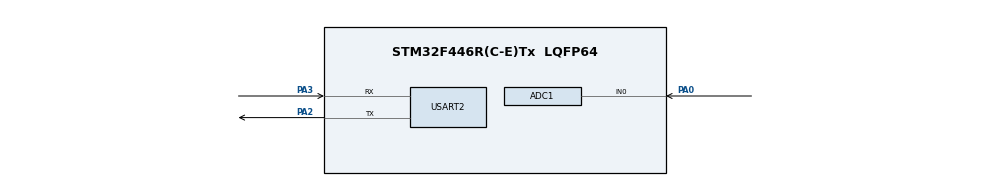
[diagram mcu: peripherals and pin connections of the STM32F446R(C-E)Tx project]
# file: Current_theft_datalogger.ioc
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ADC1.Channel-0\#ChannelRegularConversion=ADC_CHANNEL_0
ADC1.NbrOfConversionFlag=1
ADC1.Rank-0\#ChannelRegularConversion=1
ADC1.SamplingTime-0\#ChannelRegularConversion=ADC_SAMPLETIME_3CYCLES
ADC1.master=1
Dma.Request0=USART2_RX
Dma.Request1=USART2_TX
Dma.USART2_RX.0.Direction=DMA_PERIPH_TO_MEMORY
Dma.USART2_RX.0.FIFOMode=DMA_FIFOMODE_DISABLE
Dma.USART2_RX.0.Instance=DMA1_Stream5
Dma.USART2_RX.0.MemDataAlignment=DMA_MDATAALIGN_BYTE
Dma.USART2_RX.0.MemInc=DMA_MINC_ENABLE
Dma.USART2_RX.0.Mode=DMA_NORMAL
Dma.USART2_RX.0.PeriphDataAlignment=DMA_PDATAALIGN_BYTE
Dma.USART2_RX.0.PeriphInc=DMA_PINC_DISABLE
Dma.USART2_RX.0.Priority=DMA_PRIORITY_LOW
Dma.USART2_TX.1.Direction=DMA_MEMORY_TO_PERIPH
Dma.USART2_TX.1.FIFOMode=DMA_FIFOMODE_DISABLE
Dma.USART2_TX.1.Instance=DMA1_Stream6
Dma.USART2_TX.1.MemDataAlignment=DMA_MDATAALIGN_BYTE
Dma.USART2_TX.1.MemInc=DMA_MINC_ENABLE
Dma.USART2_TX.1.Mode=DMA_NORMAL
Dma.USART2_TX.1.PeriphDataAlignment=DMA_PDATAALIGN_BYTE
Dma.USART2_TX.1.PeriphInc=DMA_PINC_DISABLE
Dma.USART2_TX.1.Priority=DMA_PRIORITY_LOW
Mcu.Family=STM32F4
Mcu.Name=STM32F446R(C-E)Tx
Mcu.Package=LQFP64
NVIC.DMA1_Stream5_IRQn=true\:0\:0\:false\:false\:true\:false\:true\:true
NVIC.DMA1_Stream6_IRQn=true\:0\:0\:false\:false\:true\:false\:true\:true
NVIC.PriorityGroup=NVIC_PRIORITYGROUP_4
PA0-WKUP.Signal=ADCx_IN0
PA2.Mode=Asynchronous
PA2.Signal=USART2_TX
PA3.Mode=Asynchronous
PA3.Signal=USART2_RX
PC13.Mode=SYS_WakeUp1
PC13.Signal=SYS_WKUP1
PC14-OSC32_IN.Mode=LSE-External-Oscillator
PC14-OSC32_IN.Signal=RCC_OSC32_IN
PC15-OSC32_OUT.Mode=LSE-External-Oscillator
PC15-OSC32_OUT.Signal=RCC_OSC32_OUT
PH0-OSC_IN.Mode=HSE-External-Oscillator
PH0-OSC_IN.Signal=RCC_OSC_IN
PH1-OSC_OUT.Mode=HSE-External-Oscillator
PH1-OSC_OUT.Signal=RCC_OSC_OUT
ProjectManager.HeapSize=0x200
ProjectManager.StackSize=0x400
ProjectManager.TargetToolchain=STM32CubeIDE
RCC.CortexFreq_Value=16000000
RCC.USBFreq_Value=96000000
RCC.VCOOutputFreq_Value=192000000
SH.ADCx_IN0.0=ADC1_IN0,IN0
USART2.VirtualMode=VM_ASYNC
board=custom

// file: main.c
/* USER CODE BEGIN Header */
/**
  ******************************************************************************
  * @file           : main.c
  * @brief          : ACS712 Current Sensor Example with UART Print
  ******************************************************************************
  * @attention
  *
  * This code reads ACS712 output on PA0, converts to current, and prints over UART2.
  *
  ******************************************************************************
  */
/* USER CODE END Header */

#include "main.h"
#include <stdio.h>
#include <string.h>
#include "NanoEdgeAI.h"
#define VREF             3.3f
#define ADC_RESOLUTION   4095.0f
#define ACS_SENSITIVITY  0.185f   // 5A version = 185 mV/A

ADC_HandleTypeDef hadc1;
UART_HandleTypeDef huart2;

float ACS_OFFSET_V = 2.50f;   // Will calibrate at startup
char msg[64];

void SystemClock_Config(void);
static void MX_GPIO_Init(void);
static void MX_USART2_UART_Init(void);
static void MX_ADC1_Init(void);
void Error_Handler(void);

int main(void)
{
  /* MCU Configuration--------------------------------------------------------*/
  HAL_Init();
  SystemClock_Config();
  MX_GPIO_Init();
  MX_USART2_UART_Init();
  MX_ADC1_Init();

  /* Start ADC */
  HAL_ADC_Start(&hadc1);

  /* Calibrate ACS712 offset at startup (average 100 samples, no current) */
  uint32_t sum = 0;
  for (int i = 0; i < 100; i++)
  {
    HAL_ADC_PollForConversion(&hadc1, HAL_MAX_DELAY);
    sum += HAL_ADC_GetValue(&hadc1);
    HAL_Delay(1);
  }
  uint32_t avgAdc = sum / 100;
  ACS_OFFSET_V = ((float)avgAdc * VREF) / ADC_RESOLUTION;

  /* UART test */
  char *startMsg = "ACS712 Current Sensor Started\r\n";
  HAL_UART_Transmit(&huart2, (uint8_t*)startMsg, strlen(startMsg), HAL_MAX_DELAY);

  /* Infinite loop */
  while (1)
  {
    if(HAL_ADC_PollForConversion(&hadc1, 10) == HAL_OK)
    {
      uint32_t adcVal = HAL_ADC_GetValue(&hadc1);
      float voltage = ((float)adcVal * VREF) / ADC_RESOLUTION;
      float current = (voltage - ACS_OFFSET_V) / ACS_SENSITIVITY;

      int len = snprintf(msg, sizeof(msg),
                         "ADC=%lu | V=%.3f V | I=%.3f A\r\n",
                         adcVal, voltage, current);
      if(len > 0)
      {
        HAL_UART_Transmit(&huart2, (uint8_t*)msg, len, HAL_MAX_DELAY);
      }
    }

    HAL_Delay(200);
  }
}

/* System Clock Configuration */
void SystemClock_Config(void)
{
  RCC_OscInitTypeDef RCC_OscInitStruct = {0};
  RCC_ClkInitTypeDef RCC_ClkInitStruct = {0};

  __HAL_RCC_PWR_CLK_ENABLE();
  __HAL_PWR_VOLTAGESCALING_CONFIG(PWR_REGULATOR_VOLTAGE_SCALE3);

  RCC_OscInitStruct.OscillatorType = RCC_OSCILLATORTYPE_HSI;
  RCC_OscInitStruct.HSIState = RCC_HSI_ON;
  RCC_OscInitStruct.HSICalibrationValue = RCC_HSICALIBRATION_DEFAULT;
  RCC_OscInitStruct.PLL.PLLState = RCC_PLL_ON;
  RCC_OscInitStruct.PLL.PLLSource = RCC_PLLSOURCE_HSI;
  RCC_OscInitStruct.PLL.PLLM = 16;
  RCC_OscInitStruct.PLL.PLLN = 336;
  RCC_OscInitStruct.PLL.PLLP = RCC_PLLP_DIV4;
  RCC_OscInitStruct.PLL.PLLQ = 2;
  RCC_OscInitStruct.PLL.PLLR = 2;
  if(HAL_RCC_OscConfig(&RCC_OscInitStruct) != HAL_OK) Error_Handler();

  RCC_ClkInitStruct.ClockType = RCC_CLOCKTYPE_HCLK|RCC_CLOCKTYPE_SYSCLK
                              |RCC_CLOCKTYPE_PCLK1|RCC_CLOCKTYPE_PCLK2;
  RCC_ClkInitStruct.SYSCLKSource = RCC_SYSCLKSOURCE_PLLCLK;
  RCC_ClkInitStruct.AHBCLKDivider = RCC_SYSCLK_DIV1;
  RCC_ClkInitStruct.APB1CLKDivider = RCC_HCLK_DIV2;
  RCC_ClkInitStruct.APB2CLKDivider = RCC_HCLK_DIV1;
  if(HAL_RCC_ClockConfig(&RCC_ClkInitStruct, FLASH_LATENCY_2) != HAL_OK) Error_Handler();
}

/* ADC1 init function */
static void MX_ADC1_Init(void)
{
  ADC_ChannelConfTypeDef sConfig = {0};

  hadc1.Instance = ADC1;
  hadc1.Init.ClockPrescaler = ADC_CLOCK_SYNC_PCLK_DIV4;
  hadc1.Init.Resolution = ADC_RESOLUTION_12B;
  hadc1.Init.ScanConvMode = DISABLE;
  hadc1.Init.ContinuousConvMode = ENABLE;
  hadc1.Init.DiscontinuousConvMode = DISABLE;
  hadc1.Init.ExternalTrigConvEdge = ADC_EXTERNALTRIGCONVEDGE_NONE;
  hadc1.Init.ExternalTrigConv = ADC_SOFTWARE_START;
  hadc1.Init.DataAlign = ADC_DATAALIGN_RIGHT;
  hadc1.Init.NbrOfConversion = 1;
  hadc1.Init.DMAContinuousRequests = DISABLE;
  hadc1.Init.EOCSelection = ADC_EOC_SINGLE_CONV;
  if(HAL_ADC_Init(&hadc1) != HAL_OK) Error_Handler();

  sConfig.Channel = ADC_CHANNEL_0;
  sConfig.Rank = 1;
  sConfig.SamplingTime = ADC_SAMPLETIME_3CYCLES;
  if(HAL_ADC_ConfigChannel(&hadc1, &sConfig) != HAL_OK) Error_Handler();
}

/* USART2 init function */
static void MX_USART2_UART_Init(void)
{
  huart2.Instance = USART2;
  huart2.Init.BaudRate = 115200;
  huart2.Init.WordLength = UART_WORDLENGTH_8B;
  huart2.Init.StopBits = UART_STOPBITS_1;
  huart2.Init.Parity = UART_PARITY_NONE;
  huart2.Init.Mode = UART_MODE_TX_RX;
  huart2.Init.HwFlowCtl = UART_HWCONTROL_NONE;
  huart2.Init.OverSampling = UART_OVERSAMPLING_16;
  if(HAL_UART_Init(&huart2) != HAL_OK) Error_Handler();
}

/* GPIO init function */
static void MX_GPIO_Init(void)
{
  __HAL_RCC_GPIOC_CLK_ENABLE();
  __HAL_RCC_GPIOH_CLK_ENABLE();
  __HAL_RCC_GPIOA_CLK_ENABLE();
  __HAL_RCC_GPIOB_CLK_ENABLE();
}

/* Error Handler */
void Error_Handler(void)
{
  __disable_irq();
  while(1) {}
}
